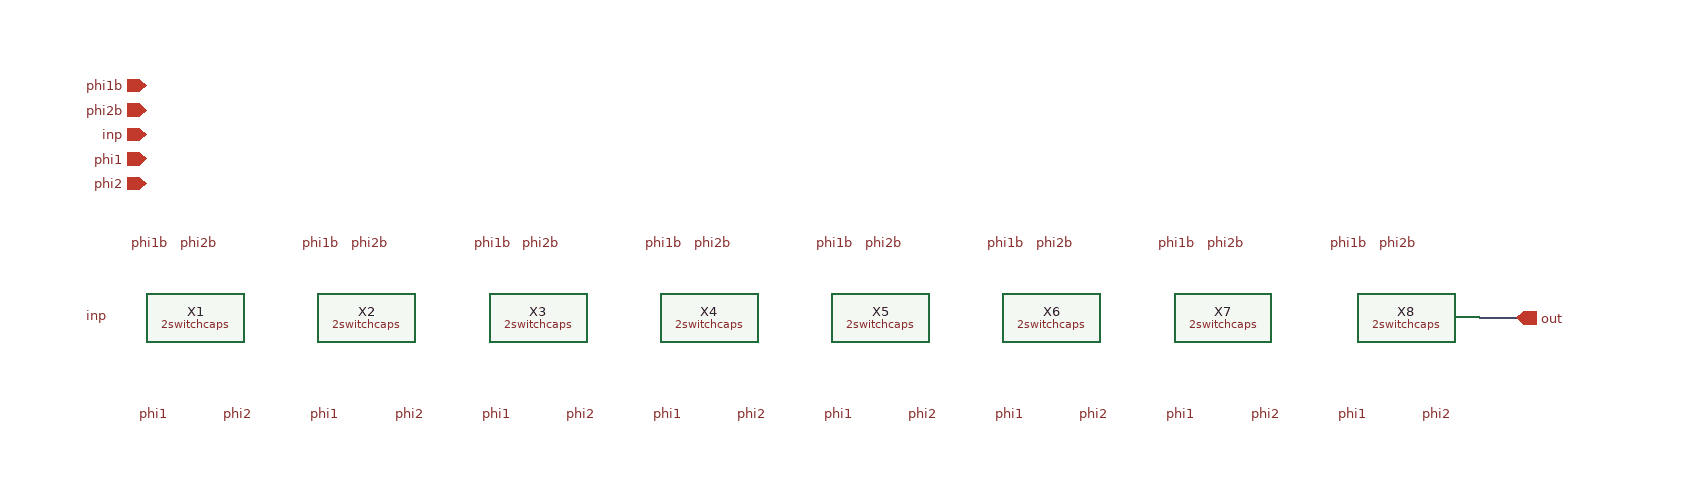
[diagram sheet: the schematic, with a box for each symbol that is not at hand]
v {xschem version=2.9.9 file_version=1.2 }
G {}
K {}
V {}
S {}
E {}
N 1170 -100 1200 -100 { lab=out}
C {tryandtest/2switchcaps.sym} 120 -100 0 0 {name=X1 Wcap=Wcap Lcap=Lcap}
C {devices/ipin.sym} 80 -250 0 0 {name=p1 lab=inp}
C {devices/ipin.sym} 80 -230 0 0 {name=p3 lab=phi1}
C {devices/ipin.sym} 80 -210 0 0 {name=p4 lab=phi2}
C {devices/lab_pin.sym} 50 -100 0 0 {name=l2 sig_type=std_logic lab=inp}
C {devices/lab_pin.sym} 100 -20 0 0 {name=l3 sig_type=std_logic lab=phi1}
C {devices/lab_pin.sym} 140 -20 2 0 {name=l4 sig_type=std_logic lab=phi2}
C {devices/lab_pin.sym} 100 -160 0 0 {name=l11 sig_type=std_logic lab=phi1b}
C {devices/lab_pin.sym} 140 -160 1 0 {name=l12 sig_type=std_logic lab=phi2b}
C {devices/opin.sym} 1200 -100 0 0 {name=p5 lab=out}
C {devices/ipin.sym} 80 -290 0 0 {name=p2 lab=phi1b}
C {devices/ipin.sym} 80 -270 0 0 {name=p6 lab=phi2b}
C {tryandtest/2switchcaps.sym} 260 -100 0 0 {name=X2 Wcap=Wcap Lcap=Lcap}
C {devices/lab_pin.sym} 240 -20 0 0 {name=l1 sig_type=std_logic lab=phi1}
C {devices/lab_pin.sym} 280 -20 2 0 {name=l5 sig_type=std_logic lab=phi2}
C {devices/lab_pin.sym} 240 -160 0 0 {name=l6 sig_type=std_logic lab=phi1b}
C {devices/lab_pin.sym} 280 -160 1 0 {name=l7 sig_type=std_logic lab=phi2b}
C {tryandtest/2switchcaps.sym} 400 -100 0 0 {name=X3 Wcap=Wcap Lcap=Lcap}
C {devices/lab_pin.sym} 380 -20 0 0 {name=l8 sig_type=std_logic lab=phi1}
C {devices/lab_pin.sym} 420 -20 2 0 {name=l9 sig_type=std_logic lab=phi2}
C {devices/lab_pin.sym} 380 -160 0 0 {name=l10 sig_type=std_logic lab=phi1b}
C {devices/lab_pin.sym} 420 -160 1 0 {name=l13 sig_type=std_logic lab=phi2b}
C {tryandtest/2switchcaps.sym} 540 -100 0 0 {name=X4 Wcap=Wcap Lcap=Lcap}
C {devices/lab_pin.sym} 520 -20 0 0 {name=l14 sig_type=std_logic lab=phi1}
C {devices/lab_pin.sym} 560 -20 2 0 {name=l15 sig_type=std_logic lab=phi2}
C {devices/lab_pin.sym} 520 -160 0 0 {name=l16 sig_type=std_logic lab=phi1b}
C {devices/lab_pin.sym} 560 -160 1 0 {name=l17 sig_type=std_logic lab=phi2b}
C {tryandtest/2switchcaps.sym} 680 -100 0 0 {name=X5 Wcap=Wcap Lcap=Lcap}
C {devices/lab_pin.sym} 660 -20 0 0 {name=l18 sig_type=std_logic lab=phi1}
C {devices/lab_pin.sym} 700 -20 2 0 {name=l19 sig_type=std_logic lab=phi2}
C {devices/lab_pin.sym} 660 -160 0 0 {name=l20 sig_type=std_logic lab=phi1b}
C {devices/lab_pin.sym} 700 -160 1 0 {name=l21 sig_type=std_logic lab=phi2b}
C {tryandtest/2switchcaps.sym} 820 -100 0 0 {name=X6 Wcap=Wcap Lcap=Lcap}
C {devices/lab_pin.sym} 800 -20 0 0 {name=l22 sig_type=std_logic lab=phi1}
C {devices/lab_pin.sym} 840 -20 2 0 {name=l23 sig_type=std_logic lab=phi2}
C {devices/lab_pin.sym} 800 -160 0 0 {name=l24 sig_type=std_logic lab=phi1b}
C {devices/lab_pin.sym} 840 -160 1 0 {name=l25 sig_type=std_logic lab=phi2b}
C {tryandtest/2switchcaps.sym} 960 -100 0 0 {name=X7 Wcap=Wcap Lcap=Lcap}
C {devices/lab_pin.sym} 940 -20 0 0 {name=l26 sig_type=std_logic lab=phi1}
C {devices/lab_pin.sym} 980 -20 2 0 {name=l27 sig_type=std_logic lab=phi2}
C {devices/lab_pin.sym} 940 -160 0 0 {name=l28 sig_type=std_logic lab=phi1b}
C {devices/lab_pin.sym} 980 -160 1 0 {name=l29 sig_type=std_logic lab=phi2b}
C {tryandtest/2switchcaps.sym} 1100 -100 0 0 {name=X8 Wcap=Wcap Lcap=Lcap}
C {devices/lab_pin.sym} 1080 -20 0 0 {name=l30 sig_type=std_logic lab=phi1}
C {devices/lab_pin.sym} 1120 -20 2 0 {name=l31 sig_type=std_logic lab=phi2}
C {devices/lab_pin.sym} 1080 -160 0 0 {name=l32 sig_type=std_logic lab=phi1b}
C {devices/lab_pin.sym} 1120 -160 1 0 {name=l33 sig_type=std_logic lab=phi2b}
